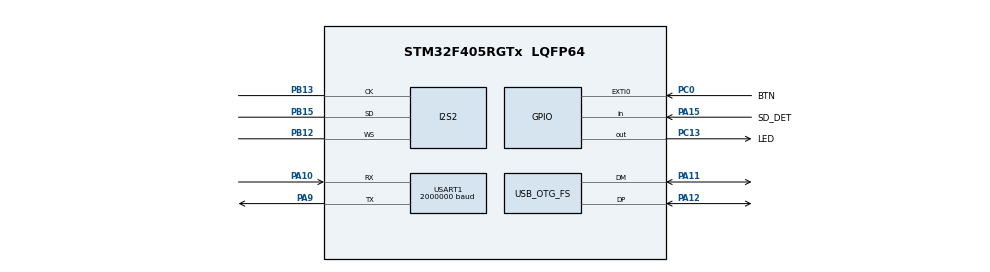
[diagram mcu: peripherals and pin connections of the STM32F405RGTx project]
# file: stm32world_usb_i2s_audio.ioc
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ARM.CMSIS.5.6.0.CMSISJjDSP=Library
Dma.Request0=SPI2_TX
Dma.SPI2_TX.0.Direction=DMA_MEMORY_TO_PERIPH
Dma.SPI2_TX.0.FIFOMode=DMA_FIFOMODE_DISABLE
Dma.SPI2_TX.0.Instance=DMA1_Stream4
Dma.SPI2_TX.0.MemDataAlignment=DMA_MDATAALIGN_HALFWORD
Dma.SPI2_TX.0.MemInc=DMA_MINC_ENABLE
Dma.SPI2_TX.0.Mode=DMA_CIRCULAR
Dma.SPI2_TX.0.PeriphDataAlignment=DMA_PDATAALIGN_HALFWORD
Dma.SPI2_TX.0.PeriphInc=DMA_PINC_DISABLE
Dma.SPI2_TX.0.Priority=DMA_PRIORITY_MEDIUM
I2S2.AudioFreq=I2S_AUDIOFREQ_96K
I2S2.DataFormat=I2S_DATAFORMAT_16B
I2S2.ErrorAudioFreq=0.15 %
I2S2.FullDuplexMode=I2S_FULLDUPLEXMODE_DISABLE
I2S2.Instance=SPI$Index
I2S2.RealAudioFreq=96.153 KHz
I2S2.Standard=I2S_STANDARD_PHILIPS
I2S2.VirtualMode=I2S_MODE_MASTER
Mcu.Family=STM32F4
Mcu.Name=STM32F405RGTx
Mcu.Package=LQFP64
NVIC.DMA1_Stream4_IRQn=true\:0\:0\:false\:false\:true\:false\:true\:true
NVIC.OTG_FS_IRQn=true\:0\:0\:false\:false\:true\:false\:true\:true
NVIC.PriorityGroup=NVIC_PRIORITYGROUP_4
PA10.Mode=Asynchronous
PA10.Signal=USART1_RX
PA11.Mode=Device_Only
PA11.Signal=USB_OTG_FS_DM
PA12.Mode=Device_Only
PA12.Signal=USB_OTG_FS_DP
PA13.Mode=Trace_Asynchronous_SW
PA13.Signal=SYS_JTMS-SWDIO
PA14.Mode=Trace_Asynchronous_SW
PA14.Signal=SYS_JTCK-SWCLK
PA15.GPIO_Label=SD_DET
PA15.Signal=GPIO_Input
PA9.Mode=Asynchronous
PA9.Signal=USART1_TX
PB12.Mode=Half_Duplex_Master
PB12.Signal=I2S2_WS
PB13.Mode=Half_Duplex_Master
PB13.Signal=I2S2_CK
PB15.Mode=Half_Duplex_Master
PB15.Signal=I2S2_SD
PB3.Mode=Trace_Asynchronous_SW
PB3.Signal=SYS_JTDO-SWO
PC0.GPIO_Label=BTN
PC0.Signal=GPXTI0
PC13-ANTI_TAMP.GPIO_Label=LED
PC13-ANTI_TAMP.GPIO_ModeDefaultOutputPP=GPIO_MODE_OUTPUT_OD
PC13-ANTI_TAMP.GPIO_PuPd=GPIO_NOPULL
PC13-ANTI_TAMP.PinState=GPIO_PIN_SET
PC13-ANTI_TAMP.Signal=GPIO_Output
PH0-OSC_IN.Mode=HSE-External-Oscillator
PH0-OSC_IN.Signal=RCC_OSC_IN
PH1-OSC_OUT.Mode=HSE-External-Oscillator
PH1-OSC_OUT.Signal=RCC_OSC_OUT
ProjectManager.HeapSize=0x200
ProjectManager.StackSize=0x400
ProjectManager.TargetToolchain=STM32CubeIDE
RCC.48MHZClocksFreq_Value=48000000
RCC.AHBFreq_Value=72000000
RCC.APB1CLKDivider=RCC_HCLK_DIV2
RCC.APB1Freq_Value=36000000
RCC.APB1TimFreq_Value=72000000
RCC.APB2Freq_Value=72000000
RCC.APB2TimFreq_Value=72000000
RCC.CortexFreq_Value=72000000
RCC.HCLKFreq_Value=72000000
RCC.HSE_VALUE=16000000
RCC.HSI_VALUE=16000000
RCC.LSE_VALUE=32768
RCC.PLLI2SN=120
RCC.PLLM=8
RCC.PLLN=72
RCC.PLLQ=3
RCC.SYSCLKFreq_VALUE=72000000
RCC.SYSCLKSource=RCC_SYSCLKSOURCE_PLLCLK
RCC.VCOOutputFreq_Value=144000000
USART1.BaudRate=2000000
USART1.VirtualMode=VM_ASYNC
USB_DEVICE.CLASS_NAME_FS=AUDIO
USB_DEVICE.MANUFACTURER_STRING-AUDIO_FS=STM32World
USB_DEVICE.PRODUCT_STRING_AUDIO_FS=STM32 Audio
USB_DEVICE.USBD_AUDIO_FREQ-AUDIO_FS=48000
USB_DEVICE.USBD_SELF_POWERED-AUDIO_FS=0
USB_DEVICE.VirtualMode-AUDIO_FS=Audio
USB_DEVICE.VirtualModeFS=Audio_FS
USB_OTG_FS.VirtualMode=Device_Only
VP_ARM.CMSIS_VS_CMSISJjDSP_1.7.0_5.6.0.Mode=CMSISJjDSP
VP_USB_DEVICE_VS_USB_DEVICE_AUDIO_FS.Mode=AUDIO_FS
board=custom

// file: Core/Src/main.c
/* USER CODE BEGIN Header */
/**
 ******************************************************************************
 * @file           : main.c
 * @brief          : Main program body
 ******************************************************************************
 * @attention
 *
 * Copyright (c) 2025 Lars Boegild Thomsen <lth@stm32world.com>
 * All rights reserved.
 *
 * This software is licensed under terms that can be found in the LICENSE file
 * in the root directory of this software component.
 * If no LICENSE file comes with this software, it is provided AS-IS.
 *
 ******************************************************************************
 */
/* USER CODE END Header */
#include "main.h"
#include "usb_device.h"

/* USER CODE BEGIN Includes */
#include <stdio.h>
#include <math.h>
#include "arm_math.h"
/* USER CODE END Includes */

/* USER CODE BEGIN PD */

#define TAU 6.28318530717958647692
#define I2S_DMA_BUFFER_SAMPLES 480
#define I2S_DMA_BUFFER_SIZE 2 * 2 * I2S_DMA_BUFFER_SAMPLES // 2 full buffers L+R samples
#define SAMPLE_FREQ 48000
#define OUTPUT_MID 32768

/* USER CODE END PD */

I2S_HandleTypeDef hi2s2;
DMA_HandleTypeDef hdma_spi2_tx;

UART_HandleTypeDef huart1;

/* USER CODE BEGIN PV */

//const float two_pi = 2 * M_PI;
float angle[2] = {
        0,
        0
};

float angle_change[2] = {
        100.0 * (TAU / SAMPLE_FREQ), // left
        50.0 * (TAU / SAMPLE_FREQ)  // right
};

float amplification[2] = {
        1,
        0.4
};

const char total_uptime_filename[] = "uptime.dat";
const char tick_filename[] = "tick.txt";

int16_t i2s_dma_buffer[I2S_DMA_BUFFER_SIZE];

//int16_t *dma_buffer_to_fill;

uint8_t dma_buffer_processing = 0;
uint32_t dma_overflow = 0;

uint32_t i2c_cb, i2c_hcb;
uint32_t total_uptime;

uint8_t open_next_file = 1;

//FRESULT res;
//DIR dir;
//FIL music_file;
//FILINFO music_file_info;

/* USER CODE END PV */

void SystemClock_Config(void);
static void MX_GPIO_Init(void);
static void MX_DMA_Init(void);
static void MX_USART1_UART_Init(void);
static void MX_I2S2_Init(void);

/* USER CODE BEGIN 0 */

// Send printf to uart1
int _write(int fd, char *ptr, int len) {
    HAL_StatusTypeDef hstatus;

    if (fd == 1 || fd == 2) {
        hstatus = HAL_UART_Transmit(&huart1, (uint8_t*) ptr, len, HAL_MAX_DELAY);
        if (hstatus == HAL_OK)
            return len;
        else
            return -1;
    }
    return -1;
}

//uint8_t BSP_SD_IsDetected(void)
//{
//    __IO uint8_t status = SD_PRESENT; // Just ignore the thing
//
////    if (HAL_GPIO_ReadPin(SD_DETECT_GPIO_PORT, SD_DETECT_PIN) != GPIO_PIN_RESET) {
////        status = SD_NOT_PRESENT;
////    }
//
//    return status;
//}
//
//void ls() {
//
//    char *path;
//
//    path = ""; // where you want to list
//
//    res = f_opendir(&dir, path);
//
//#ifdef DEBUG
//    if (res != FR_OK)
//        printf("res = %d f_opendir\n", res);
//#endif
//
//    if (res == FR_OK) {
//        while (1) {
//
//            FILINFO fno;
//
//            res = f_readdir(&dir, &fno);
//
//#ifdef DEBUG
//            if (res != FR_OK)
//                printf("res = %d f_readdir\n", res);
//#endif
//
//            if ((res != FR_OK) || (fno.fname[0] == 0))
//                break;
//
//            printf("%c%c%c%c %10d %s/%s\n",
//                    ((fno.fattrib & AM_DIR) ? 'D' : '-'),
//                    ((fno.fattrib & AM_RDO) ? 'R' : '-'),
//                    ((fno.fattrib & AM_SYS) ? 'S' : '-'),
//                    ((fno.fattrib & AM_HID) ? 'H' : '-'),
//                    (int) fno.fsize, path, fno.fname);
//        }
//
//    }
//
//    uint32_t free_clusters;
//    FATFS *fs_ptr;
//
//    res = f_getfree("", &free_clusters, &fs_ptr);
//    if (res == FR_OK) {
//        uint32_t totalBlocks = (fs_ptr->n_fatent - 2) * fs_ptr->csize;
//        uint32_t freeBlocks = free_clusters * fs_ptr->csize;
//
//        printf("Total blocks: %lu (%lu Mb)\n", totalBlocks, totalBlocks / 2000);
//        printf("Free blocks : %lu (%lu Mb)\n", freeBlocks, freeBlocks / 2000);
//    } else {
//        printf("Unable to get free space\n");
//    }
//
//}

void process_buffer(int16_t *buffer) {

    dma_buffer_processing = 1;

    for (int i = 0; i < 2 * I2S_DMA_BUFFER_SAMPLES; i += 2) { // Two samples left/right per step
        buffer[i] = OUTPUT_MID * amplification[0] * arm_cos_f32(angle[0]);      // Left
        buffer[i + 1] = OUTPUT_MID * amplification[1] * arm_cos_f32(angle[1]);  // Right
        angle[0] += angle_change[0];
        angle[1] += angle_change[1];
        if (angle[0] > TAU)
            angle[0] -= TAU;
        if (angle[1] > TAU)
            angle[1] -= TAU;
    }

    dma_buffer_processing = 0;

}

void HAL_I2S_TxCpltCallback(I2S_HandleTypeDef *hi2s) {
    if (dma_buffer_processing) {
        ++dma_overflow; // Still processing previous buffer
    } else {
        process_buffer(&i2s_dma_buffer[2 * I2S_DMA_BUFFER_SAMPLES]); // Second half
        ++i2c_cb;
    }
}

void HAL_I2S_TxHalfCpltCallback(I2S_HandleTypeDef *hi2s) {
    if (dma_buffer_processing) {
        ++dma_overflow; // Still processing previous buffer
    } else {
        process_buffer(&i2s_dma_buffer[0]);
        ++i2c_hcb;
    }

}

/* USER CODE END 0 */

int main(void)
{

    /* MCU Configuration--------------------------------------------------------*/

    /* Reset of all peripherals, Initializes the Flash interface and the Systick. */
    HAL_Init();

    /* Configure the system clock */
    SystemClock_Config();

    /* Initialize all configured peripherals */
    MX_GPIO_Init();
    MX_DMA_Init();
    MX_USART1_UART_Init();
    MX_I2S2_Init();
    MX_USB_DEVICE_Init();
    /* USER CODE BEGIN 2 */

    printf("\n\n\n---------------------\nStarting music player\n");

//    printf("SD Card Information:\n");
//    printf("Block size  : %lu\n", hsd.SdCard.BlockSize);
//    printf("Block nmbr  : %lu\n", hsd.SdCard.BlockNbr);
//    printf("Card size   : %lu\n", (hsd.SdCard.BlockSize * hsd.SdCard.BlockNbr) / 1000);
//    printf("Card version: %lu\n", hsd.SdCard.CardVersion);
//
//    uint32_t wbytes, rbytes;
//
//    if (f_mount(&SDFatFS, (TCHAR const*) SDPath, 0) != FR_OK) {
//        printf("Unable to mount disk\n");
//        Error_Handler();
//    }
//
//    if (f_open(&SDFile, total_uptime_filename, FA_OPEN_EXISTING | FA_READ) == FR_OK) {
//        if (f_read(&SDFile, &total_uptime, sizeof(total_uptime), (void*) &rbytes) == FR_OK) {
//            printf("Total uptime = %lu\n", total_uptime);
//            f_close(&SDFile);
//        } else {
//            printf("Unable to read\n");
//            Error_Handler();
//        }
//    } else {
//        // File did not exist - let's create it
//        if (f_open(&SDFile, total_uptime_filename, FA_CREATE_ALWAYS | FA_WRITE) == FR_OK) {
//            if (f_write(&SDFile, &total_uptime, sizeof(total_uptime), (void*) &wbytes) == FR_OK) {
//                printf("File %s created\n", total_uptime_filename);
//                f_close(&SDFile);
//            } else {
//                printf("Unable to write\n");
//                Error_Handler();
//            }
//        } else {
//            printf("Unable to create\n");
//            Error_Handler();
//        }
//    }
//
//    // Create tick file always
//    if (f_open(&SDFile, tick_filename, FA_CREATE_ALWAYS | FA_WRITE) == FR_OK) {
//        f_close(&SDFile);
//    }

    HAL_I2S_Transmit_DMA(&hi2s2, (uint16_t*) &i2s_dma_buffer, 2 * I2S_DMA_BUFFER_SAMPLES);

    /* USER CODE END 2 */

    /* Infinite loop */
    /* USER CODE BEGIN WHILE */

    uint32_t now = 0, next_blink = 500, next_tick = 1000, loop_cnt = 0;

    while (1) {

        now = uwTick;

        if (now >= next_blink) {

            HAL_GPIO_TogglePin(LED_GPIO_Port, LED_Pin);

            next_blink = now + 500;
        }

        if (now >= next_tick) {

            printf("Tick %lu (loop=%lu hcb=%lu cb=%lu do=%lu)\n", now / 1000, loop_cnt, i2c_hcb, i2c_cb, dma_overflow);

            ++total_uptime;

//            // Update the total uptime file
//            if (f_open(&SDFile, total_uptime_filename, FA_OPEN_EXISTING | FA_WRITE) == FR_OK) {
//                if (f_write(&SDFile, &total_uptime, sizeof(total_uptime), (void*) &wbytes) != FR_OK) {
//                    printf("Unable to write\n");
//                }
//                f_close(&SDFile);
//            } else {
//                printf("Unable to open file\n");
//            }

            open_next_file = 0;

            loop_cnt = 0;
            next_tick = now + 1000;

        }

//        if (open_next_file) {
//
//            // Experimental advance to next
//            res = f_findnext(&dir, &music_file_info);
//
//            if (res != FR_OK || music_file_info.fname[0] == '\0') { // If we're out of files start again
//                res = f_findfirst(&dir, &music_file_info, "", "*.wav");
//            }
//            printf("Next file: %s\n", music_file_info.fname);
//
//            open_next_file = 0;
//
//        }

//        if (dma_buffer_to_fill) {
//
//            for (int i = 0; i < I2S_DMA_BUFFER_SAMPLES; ++i) {
//                dma_buffer_to_fill[0] = (int16_t) (amplification[0] * (OUTPUT_MID * arm_cos_f32(angle[0])));
//                dma_buffer_to_fill[1] = (int16_t) (amplification[1] * (OUTPUT_MID * arm_cos_f32(angle[1])));
//                angle[0] += angle_change[0];
//                angle[1] += angle_change[1];
//                if (angle[0] >= two_pi) {
//                    angle[0] -= two_pi;
//                }
//                if (angle[1] >= two_pi) {
//                    angle[1] -= two_pi;
//                }
//                dma_buffer_to_fill += 2;
//            }
//
//            dma_buffer_to_fill = 0;
//        }

        ++loop_cnt;

        /* USER CODE END WHILE */

    }
}

void SystemClock_Config(void)
{
    RCC_OscInitTypeDef RCC_OscInitStruct = { 0 };
    RCC_ClkInitTypeDef RCC_ClkInitStruct = { 0 };

    /** Configure the main internal regulator output voltage
     */
    __HAL_RCC_PWR_CLK_ENABLE();
    __HAL_PWR_VOLTAGESCALING_CONFIG(PWR_REGULATOR_VOLTAGE_SCALE1);

    /** Initializes the RCC Oscillators according to the specified parameters
     * in the RCC_OscInitTypeDef structure.
     */
    RCC_OscInitStruct.OscillatorType = RCC_OSCILLATORTYPE_HSE;
    RCC_OscInitStruct.HSEState = RCC_HSE_ON;
    RCC_OscInitStruct.PLL.PLLState = RCC_PLL_ON;
    RCC_OscInitStruct.PLL.PLLSource = RCC_PLLSOURCE_HSE;
    RCC_OscInitStruct.PLL.PLLM = 8;
    RCC_OscInitStruct.PLL.PLLN = 168;
    RCC_OscInitStruct.PLL.PLLP = RCC_PLLP_DIV2;
    RCC_OscInitStruct.PLL.PLLQ = 7;
    if (HAL_RCC_OscConfig(&RCC_OscInitStruct) != HAL_OK)
            {
        Error_Handler();
    }

    /** Initializes the CPU, AHB and APB buses clocks
     */
    RCC_ClkInitStruct.ClockType = RCC_CLOCKTYPE_HCLK | RCC_CLOCKTYPE_SYSCLK
            | RCC_CLOCKTYPE_PCLK1 | RCC_CLOCKTYPE_PCLK2;
    RCC_ClkInitStruct.SYSCLKSource = RCC_SYSCLKSOURCE_PLLCLK;
    RCC_ClkInitStruct.AHBCLKDivider = RCC_SYSCLK_DIV1;
    RCC_ClkInitStruct.APB1CLKDivider = RCC_HCLK_DIV4;
    RCC_ClkInitStruct.APB2CLKDivider = RCC_HCLK_DIV2;

    if (HAL_RCC_ClockConfig(&RCC_ClkInitStruct, FLASH_LATENCY_5) != HAL_OK)
            {
        Error_Handler();
    }
}

static void MX_I2S2_Init(void)
{

    hi2s2.Instance = SPI2;
    hi2s2.Init.Mode = I2S_MODE_MASTER_TX;
    hi2s2.Init.Standard = I2S_STANDARD_PHILIPS;
    hi2s2.Init.DataFormat = I2S_DATAFORMAT_16B;
    hi2s2.Init.MCLKOutput = I2S_MCLKOUTPUT_DISABLE;
    hi2s2.Init.AudioFreq = I2S_AUDIOFREQ_48K;
    hi2s2.Init.CPOL = I2S_CPOL_LOW;
    hi2s2.Init.ClockSource = I2S_CLOCK_PLL;
    hi2s2.Init.FullDuplexMode = I2S_FULLDUPLEXMODE_DISABLE;
    if (HAL_I2S_Init(&hi2s2) != HAL_OK)
            {
        Error_Handler();
    }

}

static void MX_USART1_UART_Init(void)
{

    huart1.Instance = USART1;
    huart1.Init.BaudRate = 2000000;
    huart1.Init.WordLength = UART_WORDLENGTH_8B;
    huart1.Init.StopBits = UART_STOPBITS_1;
    huart1.Init.Parity = UART_PARITY_NONE;
    huart1.Init.Mode = UART_MODE_TX_RX;
    huart1.Init.HwFlowCtl = UART_HWCONTROL_NONE;
    huart1.Init.OverSampling = UART_OVERSAMPLING_16;
    if (HAL_UART_Init(&huart1) != HAL_OK)
            {
        Error_Handler();
    }

}

static void MX_DMA_Init(void)
{

    /* DMA controller clock enable */
    __HAL_RCC_DMA1_CLK_ENABLE();

    /* DMA interrupt init */
    /* DMA1_Stream4_IRQn interrupt configuration */
    HAL_NVIC_SetPriority(DMA1_Stream4_IRQn, 0, 0);
    HAL_NVIC_EnableIRQ(DMA1_Stream4_IRQn);

}

static void MX_GPIO_Init(void)
{
    GPIO_InitTypeDef GPIO_InitStruct = { 0 };

    /* GPIO Ports Clock Enable */
    __HAL_RCC_GPIOC_CLK_ENABLE();
    __HAL_RCC_GPIOH_CLK_ENABLE();
    __HAL_RCC_GPIOB_CLK_ENABLE();
    __HAL_RCC_GPIOA_CLK_ENABLE();

    /*Configure GPIO pin Output Level */
    HAL_GPIO_WritePin(LED_GPIO_Port, LED_Pin, GPIO_PIN_SET);

    /*Configure GPIO pin : LED_Pin */
    GPIO_InitStruct.Pin = LED_Pin;
    GPIO_InitStruct.Mode = GPIO_MODE_OUTPUT_OD;
    GPIO_InitStruct.Pull = GPIO_NOPULL;
    GPIO_InitStruct.Speed = GPIO_SPEED_FREQ_LOW;
    HAL_GPIO_Init(LED_GPIO_Port, &GPIO_InitStruct);

    /*Configure GPIO pin : BTN_Pin */
    GPIO_InitStruct.Pin = BTN_Pin;
    GPIO_InitStruct.Mode = GPIO_MODE_IT_RISING;
    GPIO_InitStruct.Pull = GPIO_NOPULL;
    HAL_GPIO_Init(BTN_GPIO_Port, &GPIO_InitStruct);

    /*Configure GPIO pin : SD_DET_Pin */
    GPIO_InitStruct.Pin = SD_DET_Pin;
    GPIO_InitStruct.Mode = GPIO_MODE_INPUT;
    GPIO_InitStruct.Pull = GPIO_NOPULL;
    HAL_GPIO_Init(SD_DET_GPIO_Port, &GPIO_InitStruct);

}

void Error_Handler(void)
{
    __disable_irq();
    while (1)
    {
    }
}
